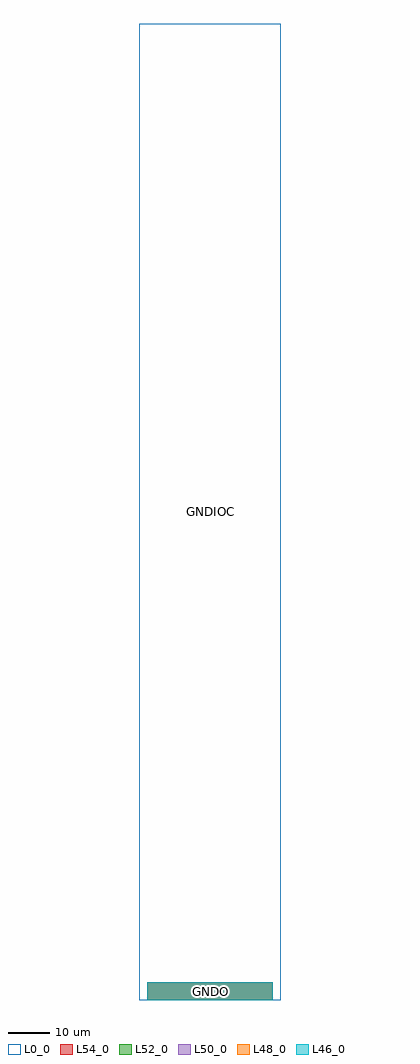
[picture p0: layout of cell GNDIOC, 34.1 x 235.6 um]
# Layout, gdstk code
import gdstk
lib = gdstk.Library(unit=1e-6, precision=1e-09)
def R(c, l, rs):  # rectangles x0, y0, x1, y1
    for r in rs: c.add(gdstk.rectangle(r[:2], r[2:], *l))
L0_0 = (0, 0)
L46_0 = (46, 0)
L48_0 = (48, 0)
L50_0 = (50, 0)
L52_0 = (52, 0)
L54_0 = (54, 0)

gndioc = lib.new_cell('GNDIOC')
R(gndioc, L0_0, [(0,0,34.1,235.6)])
R(gndioc, L46_0, [(1.91,0,32.19,4.3)])
R(gndioc, L48_0, [(1.91,0,32.19,4.3)])
R(gndioc, L50_0, [(1.91,0,32.19,4.3)])
R(gndioc, L52_0, [(1.91,0,32.19,4.3)])
R(gndioc, L54_0, [(1.91,0,32.19,4.3)])
gndioc.add(gdstk.Label('GNDIOC', (17.05,117.8), layer=0, texttype=0))
gndioc.add(gdstk.Label('GNDO', (17.05,2.15), layer=105, texttype=0))
gndioc.add(gdstk.Label('GNDO', (17.05,2.15), layer=104, texttype=0))
gndioc.add(gdstk.Label('GNDO', (17.05,2.15), layer=103, texttype=0))
gndioc.add(gdstk.Label('GNDO', (17.05,2.15), layer=102, texttype=0))
gndioc.add(gdstk.Label('GNDO', (17.05,2.15), layer=101, texttype=0))

lib.write_gds('GNDIOC.gds')
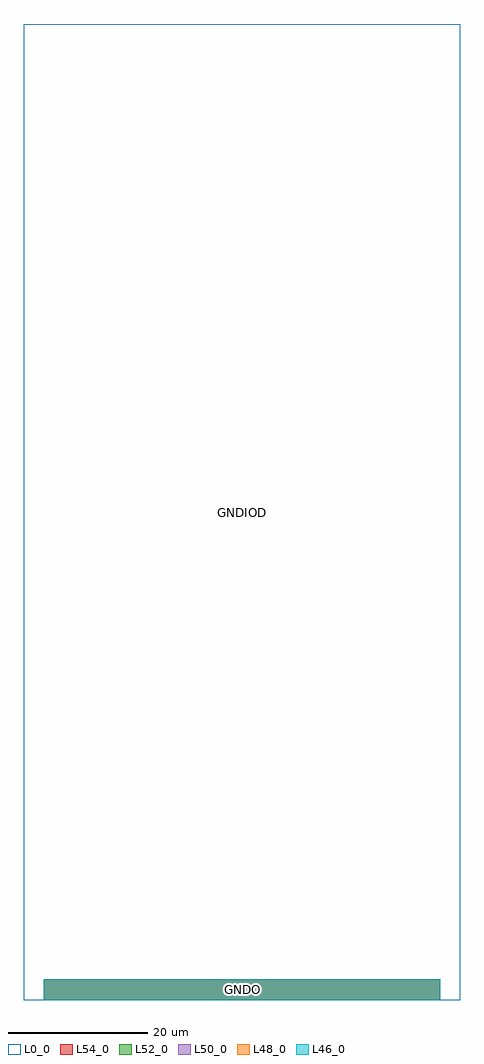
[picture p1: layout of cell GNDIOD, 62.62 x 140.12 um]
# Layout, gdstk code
import gdstk
lib = gdstk.Library(unit=1e-6, precision=1e-09)
def R(c, l, rs):  # rectangles x0, y0, x1, y1
    for r in rs: c.add(gdstk.rectangle(r[:2], r[2:], *l))
L0_0 = (0, 0)
L46_0 = (46, 0)
L48_0 = (48, 0)
L50_0 = (50, 0)
L52_0 = (52, 0)
L54_0 = (54, 0)

gndiod = lib.new_cell('GNDIOD')
R(gndiod, L0_0, [(0,0,62.62,140.12)])
R(gndiod, L46_0, [(2.85,0,59.77,3)])
R(gndiod, L48_0, [(2.85,0,59.77,3)])
R(gndiod, L50_0, [(2.85,0,59.77,3)])
R(gndiod, L52_0, [(2.85,0,59.77,3)])
R(gndiod, L54_0, [(2.85,0,59.77,3)])
gndiod.add(gdstk.Label('GNDIOD', (31.31,70.06), layer=0, texttype=0))
gndiod.add(gdstk.Label('GNDO', (31.31,1.5), layer=105, texttype=0))
gndiod.add(gdstk.Label('GNDO', (31.31,1.5), layer=104, texttype=0))
gndiod.add(gdstk.Label('GNDO', (31.31,1.5), layer=103, texttype=0))
gndiod.add(gdstk.Label('GNDO', (31.31,1.5), layer=102, texttype=0))
gndiod.add(gdstk.Label('GNDO', (31.31,1.5), layer=101, texttype=0))

lib.write_gds('GNDIOD.gds')
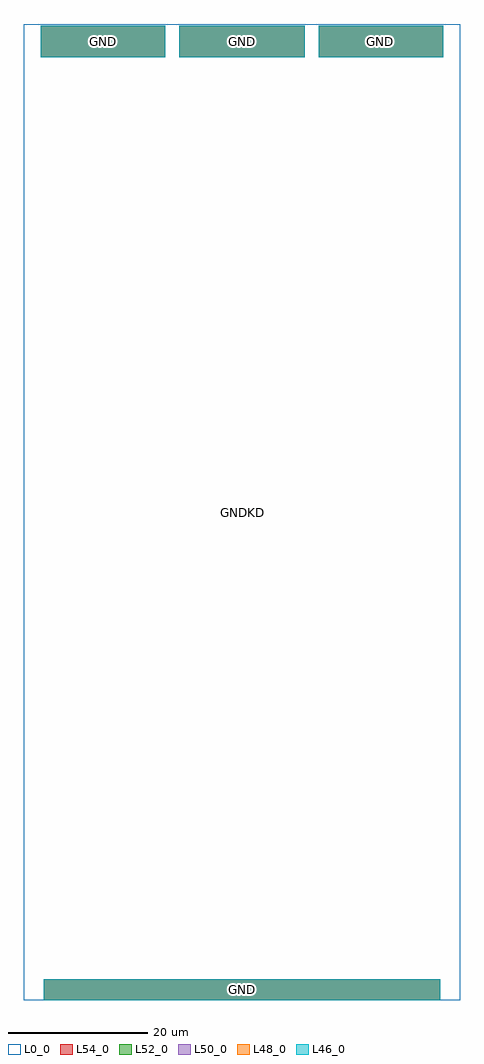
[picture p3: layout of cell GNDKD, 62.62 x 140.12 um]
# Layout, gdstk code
import gdstk
lib = gdstk.Library(unit=1e-6, precision=1e-09)
def R(c, l, rs):  # rectangles x0, y0, x1, y1
    for r in rs: c.add(gdstk.rectangle(r[:2], r[2:], *l))
L0_0 = (0, 0)
L46_0 = (46, 0)
L48_0 = (48, 0)
L50_0 = (50, 0)
L52_0 = (52, 0)
L54_0 = (54, 0)

gndkd = lib.new_cell('GNDKD')
R(gndkd, L0_0, [(0,0,62.62,140.12)])
R(gndkd, L46_0, [(2.85,0,59.77,3), (2.41,135.36,20.31,139.88), (22.31,135.36,40.31,139.88), (42.31,135.36,60.21,139.88)])
R(gndkd, L48_0, [(2.85,0,59.77,3), (2.41,135.36,20.31,139.88), (22.31,135.36,40.31,139.88), (42.31,135.36,60.21,139.88)])
R(gndkd, L50_0, [(2.85,0,59.77,3), (2.41,135.36,20.31,139.88), (22.31,135.36,40.31,139.88), (42.31,135.36,60.21,139.88)])
R(gndkd, L52_0, [(2.85,0,59.77,3), (2.41,135.36,20.31,139.88), (22.31,135.36,40.31,139.88), (42.31,135.36,60.21,139.88)])
R(gndkd, L54_0, [(2.85,0,59.77,3), (2.41,135.36,20.31,139.88), (22.31,135.36,40.31,139.88), (42.31,135.36,60.21,139.88)])
gndkd.add(gdstk.Label('GNDKD', (31.31,70.06), layer=0, texttype=0))
gndkd.add(gdstk.Label('GND', (31.31,1.5), layer=105, texttype=0))
gndkd.add(gdstk.Label('GND', (31.31,1.5), layer=104, texttype=0))
gndkd.add(gdstk.Label('GND', (31.31,1.5), layer=103, texttype=0))
gndkd.add(gdstk.Label('GND', (31.31,1.5), layer=102, texttype=0))
gndkd.add(gdstk.Label('GND', (31.31,1.5), layer=101, texttype=0))
gndkd.add(gdstk.Label('GND', (51.26,137.62), layer=105, texttype=0))
gndkd.add(gdstk.Label('GND', (51.26,137.62), layer=104, texttype=0))
gndkd.add(gdstk.Label('GND', (51.26,137.62), layer=103, texttype=0))
gndkd.add(gdstk.Label('GND', (51.26,137.62), layer=102, texttype=0))
gndkd.add(gdstk.Label('GND', (51.26,137.62), layer=101, texttype=0))
gndkd.add(gdstk.Label('GND', (31.31,137.62), layer=105, texttype=0))
gndkd.add(gdstk.Label('GND', (31.31,137.62), layer=104, texttype=0))
gndkd.add(gdstk.Label('GND', (31.31,137.62), layer=103, texttype=0))
gndkd.add(gdstk.Label('GND', (31.31,137.62), layer=102, texttype=0))
gndkd.add(gdstk.Label('GND', (31.31,137.62), layer=101, texttype=0))
gndkd.add(gdstk.Label('GND', (11.36,137.62), layer=105, texttype=0))
gndkd.add(gdstk.Label('GND', (11.36,137.62), layer=104, texttype=0))
gndkd.add(gdstk.Label('GND', (11.36,137.62), layer=103, texttype=0))
gndkd.add(gdstk.Label('GND', (11.36,137.62), layer=102, texttype=0))
gndkd.add(gdstk.Label('GND', (11.36,137.62), layer=101, texttype=0))

lib.write_gds('GNDKD.gds')
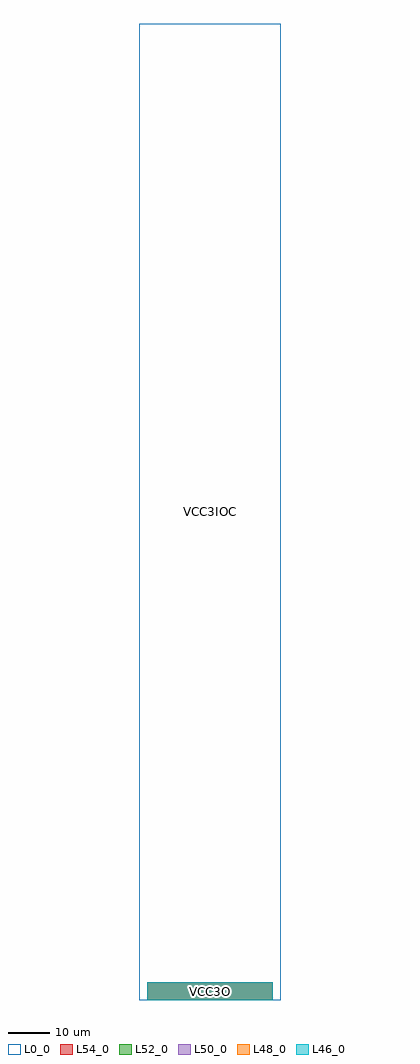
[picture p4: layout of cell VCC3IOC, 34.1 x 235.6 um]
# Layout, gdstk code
import gdstk
lib = gdstk.Library(unit=1e-6, precision=1e-09)
def R(c, l, rs):  # rectangles x0, y0, x1, y1
    for r in rs: c.add(gdstk.rectangle(r[:2], r[2:], *l))
L0_0 = (0, 0)
L46_0 = (46, 0)
L48_0 = (48, 0)
L50_0 = (50, 0)
L52_0 = (52, 0)
L54_0 = (54, 0)

vcc3ioc = lib.new_cell('VCC3IOC')
R(vcc3ioc, L0_0, [(0,0,34.1,235.6)])
R(vcc3ioc, L46_0, [(1.91,0,32.19,4.3)])
R(vcc3ioc, L48_0, [(1.91,0,32.19,4.3)])
R(vcc3ioc, L50_0, [(1.91,0,32.19,4.3)])
R(vcc3ioc, L52_0, [(1.91,0,32.19,4.3)])
R(vcc3ioc, L54_0, [(1.91,0,32.19,4.3)])
vcc3ioc.add(gdstk.Label('VCC3IOC', (17.05,117.8), layer=0, texttype=0))
vcc3ioc.add(gdstk.Label('VCC3O', (17.05,2.15), layer=105, texttype=0))
vcc3ioc.add(gdstk.Label('VCC3O', (17.05,2.15), layer=104, texttype=0))
vcc3ioc.add(gdstk.Label('VCC3O', (17.05,2.15), layer=103, texttype=0))
vcc3ioc.add(gdstk.Label('VCC3O', (17.05,2.15), layer=102, texttype=0))
vcc3ioc.add(gdstk.Label('VCC3O', (17.05,2.15), layer=101, texttype=0))

lib.write_gds('VCC3IOC.gds')
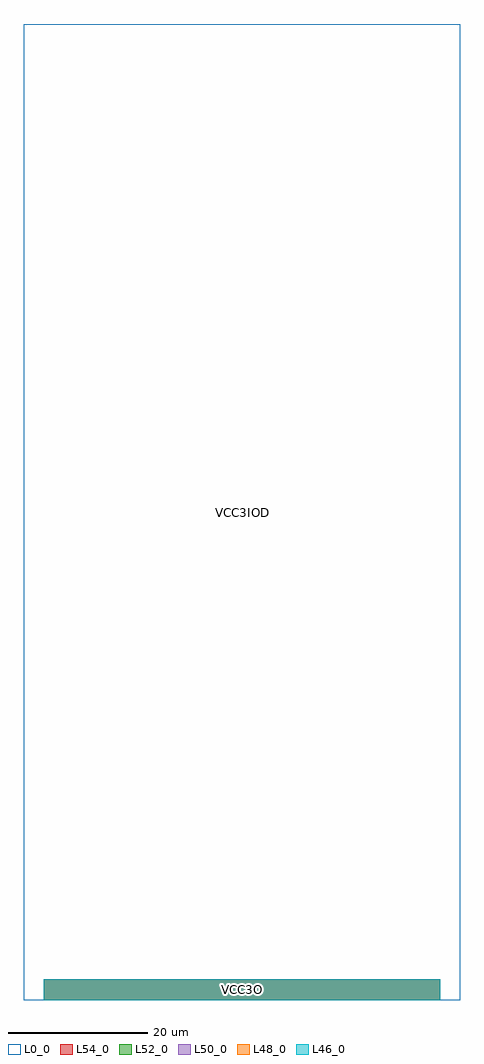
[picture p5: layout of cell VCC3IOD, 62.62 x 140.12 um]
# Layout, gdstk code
import gdstk
lib = gdstk.Library(unit=1e-6, precision=1e-09)
def R(c, l, rs):  # rectangles x0, y0, x1, y1
    for r in rs: c.add(gdstk.rectangle(r[:2], r[2:], *l))
L0_0 = (0, 0)
L46_0 = (46, 0)
L48_0 = (48, 0)
L50_0 = (50, 0)
L52_0 = (52, 0)
L54_0 = (54, 0)

vcc3iod = lib.new_cell('VCC3IOD')
R(vcc3iod, L0_0, [(0,0,62.62,140.12)])
R(vcc3iod, L46_0, [(2.85,0,59.77,3)])
R(vcc3iod, L48_0, [(2.85,0,59.77,3)])
R(vcc3iod, L50_0, [(2.85,0,59.77,3)])
R(vcc3iod, L52_0, [(2.85,0,59.77,3)])
R(vcc3iod, L54_0, [(2.85,0,59.77,3)])
vcc3iod.add(gdstk.Label('VCC3IOD', (31.31,70.06), layer=0, texttype=0))
vcc3iod.add(gdstk.Label('VCC3O', (31.31,1.5), layer=105, texttype=0))
vcc3iod.add(gdstk.Label('VCC3O', (31.31,1.5), layer=104, texttype=0))
vcc3iod.add(gdstk.Label('VCC3O', (31.31,1.5), layer=103, texttype=0))
vcc3iod.add(gdstk.Label('VCC3O', (31.31,1.5), layer=102, texttype=0))
vcc3iod.add(gdstk.Label('VCC3O', (31.31,1.5), layer=101, texttype=0))

lib.write_gds('VCC3IOD.gds')
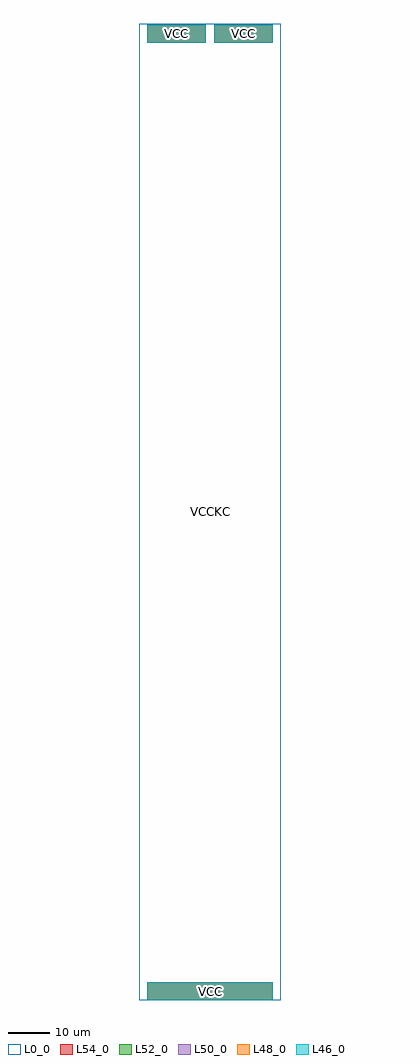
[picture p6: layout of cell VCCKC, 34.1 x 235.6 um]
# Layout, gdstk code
import gdstk
lib = gdstk.Library(unit=1e-6, precision=1e-09)
def R(c, l, rs):  # rectangles x0, y0, x1, y1
    for r in rs: c.add(gdstk.rectangle(r[:2], r[2:], *l))
L0_0 = (0, 0)
L46_0 = (46, 0)
L48_0 = (48, 0)
L50_0 = (50, 0)
L52_0 = (52, 0)
L54_0 = (54, 0)

vcckc = lib.new_cell('VCCKC')
R(vcckc, L0_0, [(0,0,34.1,235.6)])
R(vcckc, L46_0, [(1.91,0,32.19,4.3), (1.91,231.09,16.05,235.36), (18.05,231.09,32.19,235.36)])
R(vcckc, L48_0, [(1.91,0,32.19,4.3), (1.91,231.09,16.05,235.36), (18.05,231.09,32.19,235.36)])
R(vcckc, L50_0, [(1.91,0,32.19,4.3), (1.91,231.09,16.05,235.36), (18.05,231.09,32.19,235.36)])
R(vcckc, L52_0, [(1.91,0,32.19,4.3), (1.91,231.09,16.05,235.36), (18.05,231.09,32.19,235.36)])
R(vcckc, L54_0, [(1.91,0,32.19,4.3), (1.91,231.09,16.05,235.36), (18.05,231.09,32.19,235.36)])
vcckc.add(gdstk.Label('VCCKC', (17.05,117.8), layer=0, texttype=0))
vcckc.add(gdstk.Label('VCC', (17.05,2.15), layer=105, texttype=0))
vcckc.add(gdstk.Label('VCC', (17.05,2.15), layer=104, texttype=0))
vcckc.add(gdstk.Label('VCC', (17.05,2.15), layer=103, texttype=0))
vcckc.add(gdstk.Label('VCC', (17.05,2.15), layer=102, texttype=0))
vcckc.add(gdstk.Label('VCC', (17.05,2.15), layer=101, texttype=0))
vcckc.add(gdstk.Label('VCC', (25.12,233.225), layer=105, texttype=0))
vcckc.add(gdstk.Label('VCC', (25.12,233.225), layer=104, texttype=0))
vcckc.add(gdstk.Label('VCC', (25.12,233.225), layer=103, texttype=0))
vcckc.add(gdstk.Label('VCC', (25.12,233.225), layer=102, texttype=0))
vcckc.add(gdstk.Label('VCC', (25.12,233.225), layer=101, texttype=0))
vcckc.add(gdstk.Label('VCC', (8.98,233.225), layer=105, texttype=0))
vcckc.add(gdstk.Label('VCC', (8.98,233.225), layer=104, texttype=0))
vcckc.add(gdstk.Label('VCC', (8.98,233.225), layer=103, texttype=0))
vcckc.add(gdstk.Label('VCC', (8.98,233.225), layer=102, texttype=0))
vcckc.add(gdstk.Label('VCC', (8.98,233.225), layer=101, texttype=0))

lib.write_gds('VCCKC.gds')
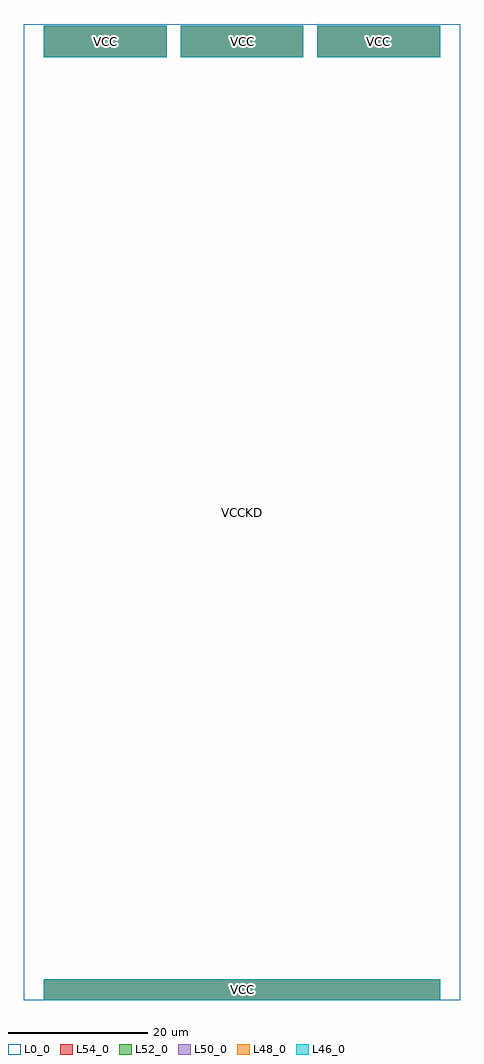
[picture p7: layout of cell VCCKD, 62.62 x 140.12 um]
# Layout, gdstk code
import gdstk
lib = gdstk.Library(unit=1e-6, precision=1e-09)
def R(c, l, rs):  # rectangles x0, y0, x1, y1
    for r in rs: c.add(gdstk.rectangle(r[:2], r[2:], *l))
def A(c, l, x, y, w, h, nx, ny, dx, dy):  # array of equal rectangles
    R(c, l, [(x+i*dx, y+j*dy, x+i*dx+w, y+j*dy+h) for i in range(nx) for j in range(ny)])
L0_0 = (0, 0)
L46_0 = (46, 0)
L48_0 = (48, 0)
L50_0 = (50, 0)
L52_0 = (52, 0)
L54_0 = (54, 0)

vcckd = lib.new_cell('VCCKD')
R(vcckd, L0_0, [(0,0,62.62,140.12)])
A(vcckd, L46_0, 2.85, 135.36, 17.64, 4.52, 3, 1, 19.64, 0)
R(vcckd, L46_0, [(2.85,0,59.77,3)])
A(vcckd, L48_0, 2.85, 135.36, 17.64, 4.52, 3, 1, 19.64, 0)
R(vcckd, L48_0, [(2.85,0,59.77,3)])
A(vcckd, L50_0, 2.85, 135.36, 17.64, 4.52, 3, 1, 19.64, 0)
R(vcckd, L50_0, [(2.85,0,59.77,3)])
A(vcckd, L52_0, 2.85, 135.36, 17.64, 4.52, 3, 1, 19.64, 0)
R(vcckd, L52_0, [(2.85,0,59.77,3)])
A(vcckd, L54_0, 2.85, 135.36, 17.64, 4.52, 3, 1, 19.64, 0)
R(vcckd, L54_0, [(2.85,0,59.77,3)])
vcckd.add(gdstk.Label('VCCKD', (31.31,70.06), layer=0, texttype=0))
vcckd.add(gdstk.Label('VCC', (31.31,1.5), layer=105, texttype=0))
vcckd.add(gdstk.Label('VCC', (31.31,1.5), layer=104, texttype=0))
vcckd.add(gdstk.Label('VCC', (31.31,1.5), layer=103, texttype=0))
vcckd.add(gdstk.Label('VCC', (31.31,1.5), layer=102, texttype=0))
vcckd.add(gdstk.Label('VCC', (31.31,1.5), layer=101, texttype=0))
vcckd.add(gdstk.Label('VCC', (11.67,137.62), layer=105, texttype=0))
vcckd.add(gdstk.Label('VCC', (11.67,137.62), layer=104, texttype=0))
vcckd.add(gdstk.Label('VCC', (11.67,137.62), layer=103, texttype=0))
vcckd.add(gdstk.Label('VCC', (11.67,137.62), layer=102, texttype=0))
vcckd.add(gdstk.Label('VCC', (11.67,137.62), layer=101, texttype=0))
vcckd.add(gdstk.Label('VCC', (31.31,137.62), layer=105, texttype=0))
vcckd.add(gdstk.Label('VCC', (31.31,137.62), layer=104, texttype=0))
vcckd.add(gdstk.Label('VCC', (31.31,137.62), layer=103, texttype=0))
vcckd.add(gdstk.Label('VCC', (31.31,137.62), layer=102, texttype=0))
vcckd.add(gdstk.Label('VCC', (31.31,137.62), layer=101, texttype=0))
vcckd.add(gdstk.Label('VCC', (50.95,137.62), layer=105, texttype=0))
vcckd.add(gdstk.Label('VCC', (50.95,137.62), layer=104, texttype=0))
vcckd.add(gdstk.Label('VCC', (50.95,137.62), layer=103, texttype=0))
vcckd.add(gdstk.Label('VCC', (50.95,137.62), layer=102, texttype=0))
vcckd.add(gdstk.Label('VCC', (50.95,137.62), layer=101, texttype=0))

lib.write_gds('VCCKD.gds')
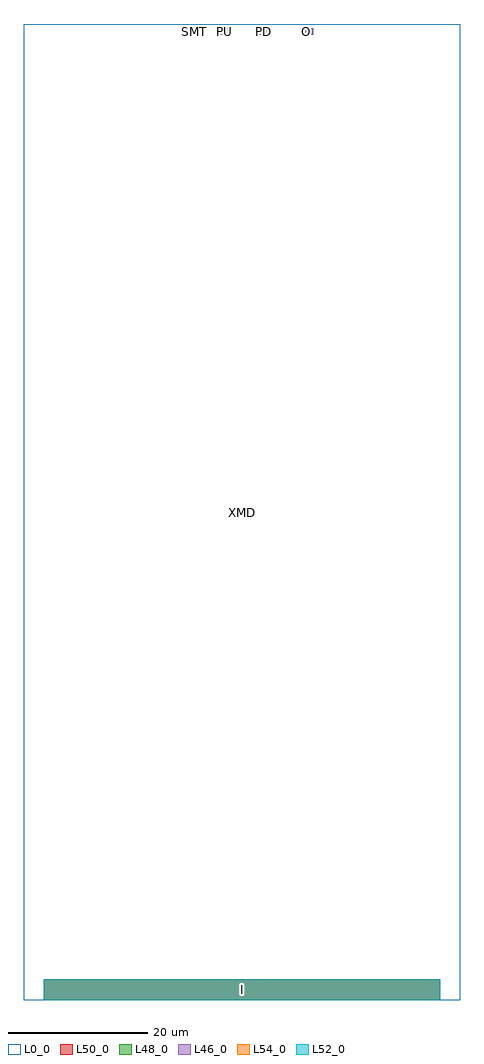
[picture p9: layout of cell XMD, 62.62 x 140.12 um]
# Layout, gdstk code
import gdstk
lib = gdstk.Library(unit=1e-6, precision=1e-09)
def R(c, l, rs):  # rectangles x0, y0, x1, y1
    for r in rs: c.add(gdstk.rectangle(r[:2], r[2:], *l))
L0_0 = (0, 0)
L46_0 = (46, 0)
L48_0 = (48, 0)
L50_0 = (50, 0)
L52_0 = (52, 0)
L54_0 = (54, 0)

xmd = lib.new_cell('XMD')
R(xmd, L0_0, [(0,0,62.62,140.12)])
R(xmd, L46_0, [(2.85,0,59.77,3), (23.55,138.6,25.43,139.5), (27.89,138.6,29.77,139.5), (33.47,138.6,35.35,139.5), (39.67,138.6,41.55,139.5)])
R(xmd, L48_0, [(2.85,0,59.77,3), (23.55,138.6,25.43,139.5), (27.89,138.6,29.77,139.5), (33.47,138.6,35.35,139.5), (39.67,138.6,41.55,139.5)])
R(xmd, L50_0, [(2.85,0,59.77,3), (23.55,138.6,25.43,139.5), (27.89,138.6,29.77,139.5), (33.47,138.6,35.35,139.5), (39.67,138.6,41.55,139.5)])
R(xmd, L52_0, [(2.85,0,59.77,3)])
R(xmd, L54_0, [(2.85,0,59.77,3)])
xmd.add(gdstk.Label('XMD', (31.31,70.06), layer=0, texttype=0))
xmd.add(gdstk.Label('O', (40.61,139.05), layer=103, texttype=0))
xmd.add(gdstk.Label('O', (40.61,139.05), layer=102, texttype=0))
xmd.add(gdstk.Label('O', (40.61,139.05), layer=101, texttype=0))
xmd.add(gdstk.Label('PD', (34.41,139.05), layer=103, texttype=0))
xmd.add(gdstk.Label('PD', (34.41,139.05), layer=102, texttype=0))
xmd.add(gdstk.Label('PD', (34.41,139.05), layer=101, texttype=0))
xmd.add(gdstk.Label('SMT', (24.49,139.05), layer=103, texttype=0))
xmd.add(gdstk.Label('SMT', (24.49,139.05), layer=102, texttype=0))
xmd.add(gdstk.Label('SMT', (24.49,139.05), layer=101, texttype=0))
xmd.add(gdstk.Label('PU', (28.83,139.05), layer=103, texttype=0))
xmd.add(gdstk.Label('PU', (28.83,139.05), layer=102, texttype=0))
xmd.add(gdstk.Label('PU', (28.83,139.05), layer=101, texttype=0))
xmd.add(gdstk.Label('I', (31.31,1.5), layer=105, texttype=0))
xmd.add(gdstk.Label('I', (31.31,1.5), layer=104, texttype=0))
xmd.add(gdstk.Label('I', (31.31,1.5), layer=103, texttype=0))
xmd.add(gdstk.Label('I', (31.31,1.5), layer=102, texttype=0))
xmd.add(gdstk.Label('I', (31.31,1.5), layer=101, texttype=0))

lib.write_gds('XMD.gds')
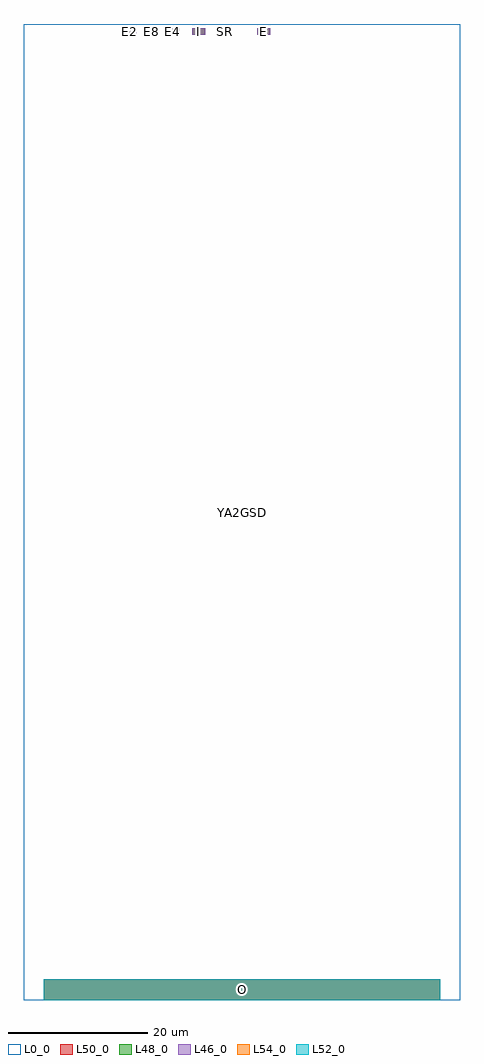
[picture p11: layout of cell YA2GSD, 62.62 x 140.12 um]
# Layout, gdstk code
import gdstk
lib = gdstk.Library(unit=1e-6, precision=1e-09)
def R(c, l, rs):  # rectangles x0, y0, x1, y1
    for r in rs: c.add(gdstk.rectangle(r[:2], r[2:], *l))
def A(c, l, x, y, w, h, nx, ny, dx, dy):  # array of equal rectangles
    R(c, l, [(x+i*dx, y+j*dy, x+i*dx+w, y+j*dy+h) for i in range(nx) for j in range(ny)])
L0_0 = (0, 0)
L46_0 = (46, 0)
L48_0 = (48, 0)
L50_0 = (50, 0)
L52_0 = (52, 0)
L54_0 = (54, 0)

ya2gsd = lib.new_cell('YA2GSD')
R(ya2gsd, L0_0, [(0,0,62.62,140.12)])
A(ya2gsd, L46_0, 14.25, 138.6, 1.88, 0.9, 3, 1, 3.1, 0)
R(ya2gsd, L46_0, [(2.85,0,59.77,3), (24.17,138.6,26.05,139.5), (27.89,138.6,29.77,139.5), (33.47,138.6,35.35,139.5)])
A(ya2gsd, L48_0, 14.25, 138.6, 1.88, 0.9, 3, 1, 3.1, 0)
R(ya2gsd, L48_0, [(2.85,0,59.77,3), (24.17,138.6,26.05,139.5), (27.89,138.6,29.77,139.5), (33.47,138.6,35.35,139.5)])
A(ya2gsd, L50_0, 14.25, 138.6, 1.88, 0.9, 3, 1, 3.1, 0)
R(ya2gsd, L50_0, [(2.85,0,59.77,3), (24.17,138.6,26.05,139.5), (27.89,138.6,29.77,139.5), (33.47,138.6,35.35,139.5)])
R(ya2gsd, L52_0, [(2.85,0,59.77,3)])
R(ya2gsd, L54_0, [(2.85,0,59.77,3)])
ya2gsd.add(gdstk.Label('YA2GSD', (31.31,70.06), layer=0, texttype=0))
ya2gsd.add(gdstk.Label('I', (25.11,139.05), layer=103, texttype=0))
ya2gsd.add(gdstk.Label('I', (25.11,139.05), layer=102, texttype=0))
ya2gsd.add(gdstk.Label('I', (25.11,139.05), layer=101, texttype=0))
ya2gsd.add(gdstk.Label('E4', (21.39,139.05), layer=103, texttype=0))
ya2gsd.add(gdstk.Label('E4', (21.39,139.05), layer=102, texttype=0))
ya2gsd.add(gdstk.Label('E4', (21.39,139.05), layer=101, texttype=0))
ya2gsd.add(gdstk.Label('E', (34.41,139.05), layer=103, texttype=0))
ya2gsd.add(gdstk.Label('E', (34.41,139.05), layer=102, texttype=0))
ya2gsd.add(gdstk.Label('E', (34.41,139.05), layer=101, texttype=0))
ya2gsd.add(gdstk.Label('SR', (28.83,139.05), layer=103, texttype=0))
ya2gsd.add(gdstk.Label('SR', (28.83,139.05), layer=102, texttype=0))
ya2gsd.add(gdstk.Label('SR', (28.83,139.05), layer=101, texttype=0))
ya2gsd.add(gdstk.Label('E8', (18.29,139.05), layer=103, texttype=0))
ya2gsd.add(gdstk.Label('E8', (18.29,139.05), layer=102, texttype=0))
ya2gsd.add(gdstk.Label('E8', (18.29,139.05), layer=101, texttype=0))
ya2gsd.add(gdstk.Label('E2', (15.19,139.05), layer=103, texttype=0))
ya2gsd.add(gdstk.Label('E2', (15.19,139.05), layer=102, texttype=0))
ya2gsd.add(gdstk.Label('E2', (15.19,139.05), layer=101, texttype=0))
ya2gsd.add(gdstk.Label('O', (31.31,1.5), layer=105, texttype=0))
ya2gsd.add(gdstk.Label('O', (31.31,1.5), layer=104, texttype=0))
ya2gsd.add(gdstk.Label('O', (31.31,1.5), layer=103, texttype=0))
ya2gsd.add(gdstk.Label('O', (31.31,1.5), layer=102, texttype=0))
ya2gsd.add(gdstk.Label('O', (31.31,1.5), layer=101, texttype=0))

lib.write_gds('YA2GSD.gds')
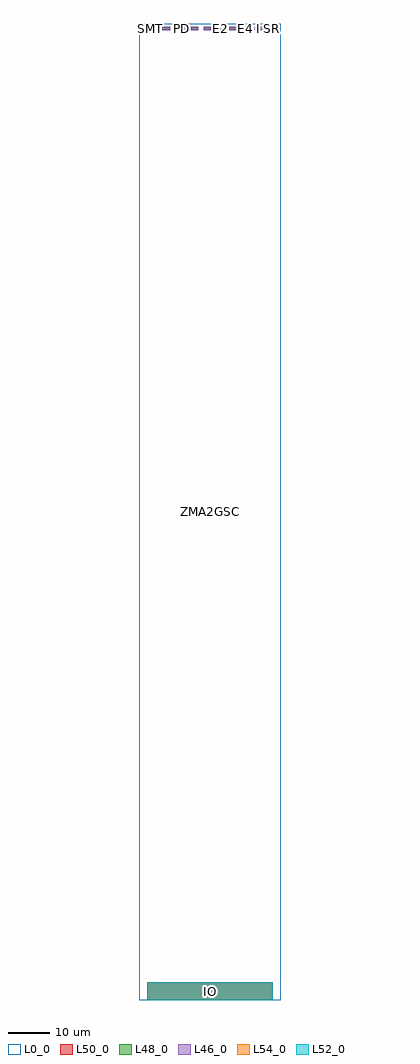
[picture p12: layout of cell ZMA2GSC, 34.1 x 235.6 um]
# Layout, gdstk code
import gdstk
lib = gdstk.Library(unit=1e-6, precision=1e-09)
def R(c, l, rs):  # rectangles x0, y0, x1, y1
    for r in rs: c.add(gdstk.rectangle(r[:2], r[2:], *l))
def A(c, l, x, y, w, h, nx, ny, dx, dy):  # array of equal rectangles
    R(c, l, [(x+i*dx, y+j*dy, x+i*dx+w, y+j*dy+h) for i in range(nx) for j in range(ny)])
L0_0 = (0, 0)
L46_0 = (46, 0)
L48_0 = (48, 0)
L50_0 = (50, 0)
L52_0 = (52, 0)
L54_0 = (54, 0)

zma2gsc = lib.new_cell('ZMA2GSC')
R(zma2gsc, L0_0, [(0,0,34.1,235.6)])
A(zma2gsc, L46_0, 1.85, 234.08, 1.88, 0.9, 3, 1, 3.72, 0)
A(zma2gsc, L46_0, 12.39, 234.08, 1.88, 0.9, 7, 1, 3.1, 0)
R(zma2gsc, L46_0, [(1.91,0,32.19,4.3)])
A(zma2gsc, L48_0, 1.85, 234.08, 1.88, 0.9, 3, 1, 3.72, 0)
A(zma2gsc, L48_0, 12.39, 234.08, 1.88, 0.9, 7, 1, 3.1, 0)
R(zma2gsc, L48_0, [(1.91,0,32.19,4.3)])
A(zma2gsc, L50_0, 1.85, 234.08, 1.88, 0.9, 3, 1, 3.72, 0)
A(zma2gsc, L50_0, 12.39, 234.08, 1.88, 0.9, 7, 1, 3.1, 0)
R(zma2gsc, L50_0, [(1.91,0,32.19,4.3)])
R(zma2gsc, L52_0, [(1.91,0,32.19,4.3)])
R(zma2gsc, L54_0, [(1.91,0,32.19,4.3)])
zma2gsc.add(gdstk.Label('ZMA2GSC', (17.05,117.8), layer=0, texttype=0))
zma2gsc.add(gdstk.Label('E2', (19.53,234.53), layer=103, texttype=0))
zma2gsc.add(gdstk.Label('E2', (19.53,234.53), layer=102, texttype=0))
zma2gsc.add(gdstk.Label('E2', (19.53,234.53), layer=101, texttype=0))
zma2gsc.add(gdstk.Label('E8', (22.63,234.53), layer=103, texttype=0))
zma2gsc.add(gdstk.Label('E8', (22.63,234.53), layer=102, texttype=0))
zma2gsc.add(gdstk.Label('E8', (22.63,234.53), layer=101, texttype=0))
zma2gsc.add(gdstk.Label('O', (16.43,234.53), layer=103, texttype=0))
zma2gsc.add(gdstk.Label('O', (16.43,234.53), layer=102, texttype=0))
zma2gsc.add(gdstk.Label('O', (16.43,234.53), layer=101, texttype=0))
zma2gsc.add(gdstk.Label('PD', (10.23,234.53), layer=103, texttype=0))
zma2gsc.add(gdstk.Label('PD', (10.23,234.53), layer=102, texttype=0))
zma2gsc.add(gdstk.Label('PD', (10.23,234.53), layer=101, texttype=0))
zma2gsc.add(gdstk.Label('E4', (25.73,234.53), layer=103, texttype=0))
zma2gsc.add(gdstk.Label('E4', (25.73,234.53), layer=102, texttype=0))
zma2gsc.add(gdstk.Label('E4', (25.73,234.53), layer=101, texttype=0))
zma2gsc.add(gdstk.Label('PU', (6.51,234.53), layer=103, texttype=0))
zma2gsc.add(gdstk.Label('PU', (6.51,234.53), layer=102, texttype=0))
zma2gsc.add(gdstk.Label('PU', (6.51,234.53), layer=101, texttype=0))
zma2gsc.add(gdstk.Label('E', (13.33,234.53), layer=103, texttype=0))
zma2gsc.add(gdstk.Label('E', (13.33,234.53), layer=102, texttype=0))
zma2gsc.add(gdstk.Label('E', (13.33,234.53), layer=101, texttype=0))
zma2gsc.add(gdstk.Label('SR', (31.93,234.53), layer=103, texttype=0))
zma2gsc.add(gdstk.Label('SR', (31.93,234.53), layer=102, texttype=0))
zma2gsc.add(gdstk.Label('SR', (31.93,234.53), layer=101, texttype=0))
zma2gsc.add(gdstk.Label('SMT', (2.79,234.53), layer=103, texttype=0))
zma2gsc.add(gdstk.Label('SMT', (2.79,234.53), layer=102, texttype=0))
zma2gsc.add(gdstk.Label('SMT', (2.79,234.53), layer=101, texttype=0))
zma2gsc.add(gdstk.Label('I', (28.83,234.53), layer=103, texttype=0))
zma2gsc.add(gdstk.Label('I', (28.83,234.53), layer=102, texttype=0))
zma2gsc.add(gdstk.Label('I', (28.83,234.53), layer=101, texttype=0))
zma2gsc.add(gdstk.Label('IO', (17.05,2.15), layer=105, texttype=0))
zma2gsc.add(gdstk.Label('IO', (17.05,2.15), layer=104, texttype=0))
zma2gsc.add(gdstk.Label('IO', (17.05,2.15), layer=103, texttype=0))
zma2gsc.add(gdstk.Label('IO', (17.05,2.15), layer=102, texttype=0))
zma2gsc.add(gdstk.Label('IO', (17.05,2.15), layer=101, texttype=0))

lib.write_gds('ZMA2GSC.gds')
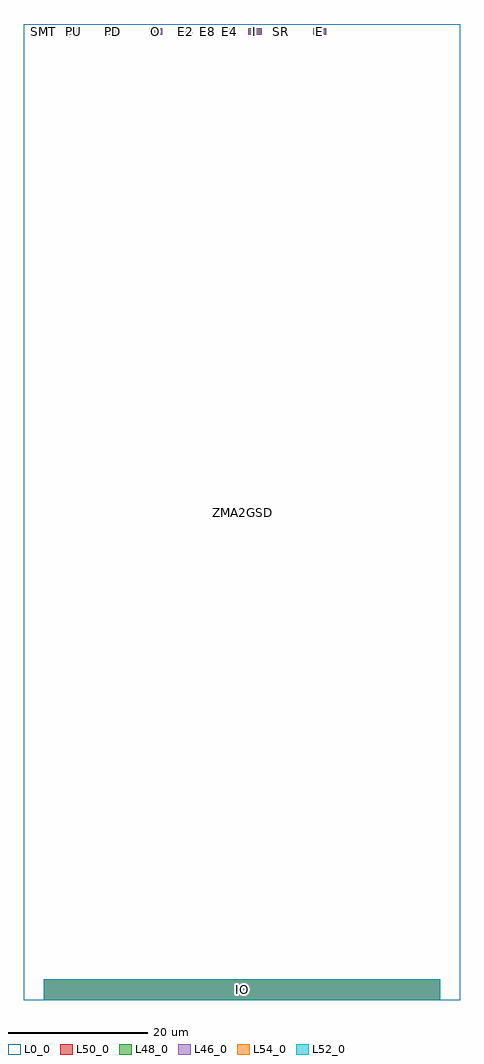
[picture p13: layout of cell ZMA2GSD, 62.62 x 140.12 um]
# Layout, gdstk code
import gdstk
lib = gdstk.Library(unit=1e-6, precision=1e-09)
def R(c, l, rs):  # rectangles x0, y0, x1, y1
    for r in rs: c.add(gdstk.rectangle(r[:2], r[2:], *l))
def A(c, l, x, y, w, h, nx, ny, dx, dy):  # array of equal rectangles
    R(c, l, [(x+i*dx, y+j*dy, x+i*dx+w, y+j*dy+h) for i in range(nx) for j in range(ny)])
L0_0 = (0, 0)
L46_0 = (46, 0)
L48_0 = (48, 0)
L50_0 = (50, 0)
L52_0 = (52, 0)
L54_0 = (54, 0)

zma2gsd = lib.new_cell('ZMA2GSD')
R(zma2gsd, L0_0, [(0,0,62.62,140.12)])
A(zma2gsd, L46_0, 22.31, 138.6, 1.88, 0.9, 3, 1, 3.1, 0)
R(zma2gsd, L46_0, [(2.85,0,59.77,3), (1.85,138.6,3.73,139.5), (6.19,138.6,8.07,139.5), (11.77,138.6,13.65,139.5), (17.97,138.6,19.85,139.5), (32.23,138.6,34.11,139.5), (35.95,138.6,37.83,139.5), (41.53,138.6,43.41,139.5)])
A(zma2gsd, L48_0, 22.31, 138.6, 1.88, 0.9, 3, 1, 3.1, 0)
R(zma2gsd, L48_0, [(2.85,0,59.77,3), (1.85,138.6,3.73,139.5), (6.19,138.6,8.07,139.5), (11.77,138.6,13.65,139.5), (17.97,138.6,19.85,139.5), (32.23,138.6,34.11,139.5), (35.95,138.6,37.83,139.5), (41.53,138.6,43.41,139.5)])
A(zma2gsd, L50_0, 22.31, 138.6, 1.88, 0.9, 3, 1, 3.1, 0)
R(zma2gsd, L50_0, [(2.85,0,59.77,3), (1.85,138.6,3.73,139.5), (6.19,138.6,8.07,139.5), (11.77,138.6,13.65,139.5), (17.97,138.6,19.85,139.5), (32.23,138.6,34.11,139.5), (35.95,138.6,37.83,139.5), (41.53,138.6,43.41,139.5)])
R(zma2gsd, L52_0, [(2.85,0,59.77,3)])
R(zma2gsd, L54_0, [(2.85,0,59.77,3)])
zma2gsd.add(gdstk.Label('ZMA2GSD', (31.31,70.06), layer=0, texttype=0))
zma2gsd.add(gdstk.Label('I', (33.17,139.05), layer=103, texttype=0))
zma2gsd.add(gdstk.Label('I', (33.17,139.05), layer=102, texttype=0))
zma2gsd.add(gdstk.Label('I', (33.17,139.05), layer=101, texttype=0))
zma2gsd.add(gdstk.Label('E4', (29.45,139.05), layer=103, texttype=0))
zma2gsd.add(gdstk.Label('E4', (29.45,139.05), layer=102, texttype=0))
zma2gsd.add(gdstk.Label('E4', (29.45,139.05), layer=101, texttype=0))
zma2gsd.add(gdstk.Label('O', (18.91,139.05), layer=103, texttype=0))
zma2gsd.add(gdstk.Label('O', (18.91,139.05), layer=102, texttype=0))
zma2gsd.add(gdstk.Label('O', (18.91,139.05), layer=101, texttype=0))
zma2gsd.add(gdstk.Label('PD', (12.71,139.05), layer=103, texttype=0))
zma2gsd.add(gdstk.Label('PD', (12.71,139.05), layer=102, texttype=0))
zma2gsd.add(gdstk.Label('PD', (12.71,139.05), layer=101, texttype=0))
zma2gsd.add(gdstk.Label('E', (42.47,139.05), layer=103, texttype=0))
zma2gsd.add(gdstk.Label('E', (42.47,139.05), layer=102, texttype=0))
zma2gsd.add(gdstk.Label('E', (42.47,139.05), layer=101, texttype=0))
zma2gsd.add(gdstk.Label('SMT', (2.79,139.05), layer=103, texttype=0))
zma2gsd.add(gdstk.Label('SMT', (2.79,139.05), layer=102, texttype=0))
zma2gsd.add(gdstk.Label('SMT', (2.79,139.05), layer=101, texttype=0))
zma2gsd.add(gdstk.Label('PU', (7.13,139.05), layer=103, texttype=0))
zma2gsd.add(gdstk.Label('PU', (7.13,139.05), layer=102, texttype=0))
zma2gsd.add(gdstk.Label('PU', (7.13,139.05), layer=101, texttype=0))
zma2gsd.add(gdstk.Label('SR', (36.89,139.05), layer=103, texttype=0))
zma2gsd.add(gdstk.Label('SR', (36.89,139.05), layer=102, texttype=0))
zma2gsd.add(gdstk.Label('SR', (36.89,139.05), layer=101, texttype=0))
zma2gsd.add(gdstk.Label('E8', (26.35,139.05), layer=103, texttype=0))
zma2gsd.add(gdstk.Label('E8', (26.35,139.05), layer=102, texttype=0))
zma2gsd.add(gdstk.Label('E8', (26.35,139.05), layer=101, texttype=0))
zma2gsd.add(gdstk.Label('E2', (23.25,139.05), layer=103, texttype=0))
zma2gsd.add(gdstk.Label('E2', (23.25,139.05), layer=102, texttype=0))
zma2gsd.add(gdstk.Label('E2', (23.25,139.05), layer=101, texttype=0))
zma2gsd.add(gdstk.Label('IO', (31.31,1.5), layer=105, texttype=0))
zma2gsd.add(gdstk.Label('IO', (31.31,1.5), layer=104, texttype=0))
zma2gsd.add(gdstk.Label('IO', (31.31,1.5), layer=103, texttype=0))
zma2gsd.add(gdstk.Label('IO', (31.31,1.5), layer=102, texttype=0))
zma2gsd.add(gdstk.Label('IO', (31.31,1.5), layer=101, texttype=0))

lib.write_gds('ZMA2GSD.gds')
